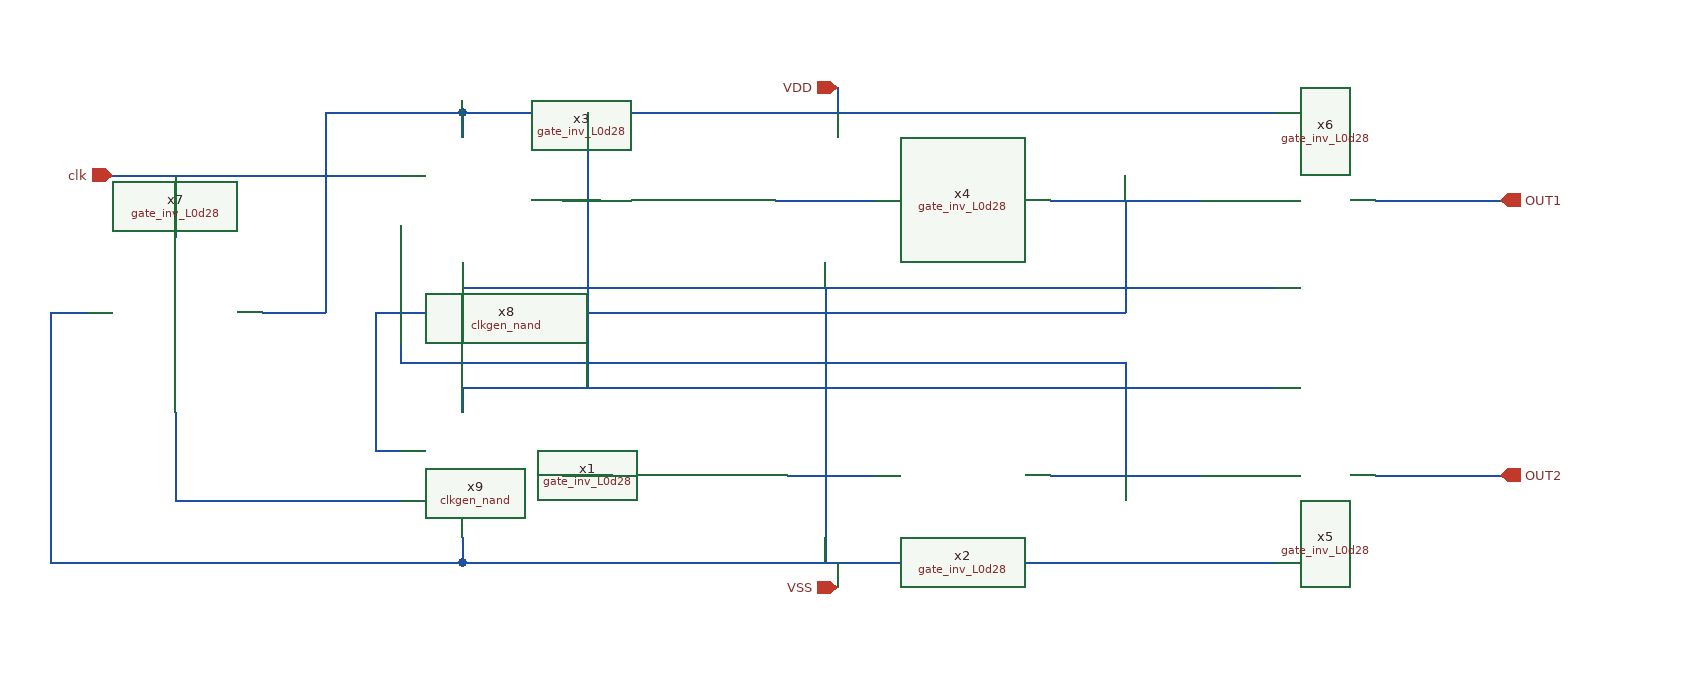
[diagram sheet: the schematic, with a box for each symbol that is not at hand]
v {xschem version=3.4.8RC file_version=1.3}
G {}
K {}
V {}
S {}
F {}
E {}
N 200 -190 280 -190 {lab=#net1}
N 420 -190 540 -190 {lab=#net2}
N 210 30 280 30 {lab=#net3}
N 420 30 540 30 {lab=#net4}
N 680 30 780 30 {lab=OUT2}
N 680 -190 780 -190 {lab=OUT1}
N 130 -40 340 -40 {lab=VDD}
N 340 -40 600 -40 {lab=VDD}
N 340 -120 600 -120 {lab=xxx}
N 120 -120 340 -120 {lab=xxx}
N 120 -260 340 -260 {lab=VDD}
N 340 -260 600 -260 {lab=VDD}
N 130 100 340 100 {lab=xxx}
N 340 100 600 100 {lab=xxx}
N 30 -190 60 -190 {lab=#net5}
N 30 30 70 30 {lab=#net6}
N -50 -260 120 -260 {lab=VDD}
N -50 -260 -50 -240 {lab=VDD}
N -50 -140 -50 -130 {lab=xxx}
N -50 -120 120 -120 {lab=xxx}
N -50 -130 -50 -120 {lab=xxx}
N -50 -40 130 -40 {lab=VDD}
N -50 -40 -50 -20 {lab=VDD}
N -50 100 130 100 {lab=xxx}
N -50 80 -50 100 {lab=xxx}
N -290 -210 -100 -210 {lab=clk}
N -210 50 -100 50 {lab=#net7}
N -120 -100 480 -100 {lab=#net2}
N -120 -80 -120 10 {lab=#net2}
N -120 10 -100 10 {lab=#net2}
N -120 -100 -120 -80 {lab=#net2}
N 480 -190 480 -100 {lab=#net2}
N -280 -210 -280 -160 {lab=clk}
N -330 -210 -290 -210 {lab=clk}
N -280 50 -210 50 {lab=#net7}
N -280 -20 -280 50 {lab=#net7}
N 480 -60 480 30 {lab=#net4}
N -100 -60 480 -60 {lab=#net4}
N -100 -170 -100 -60 {lab=#net4}
N 250 100 250 120 {lab=xxx}
N 250 -280 250 -260 {lab=VDD}
N 50 -260 50 -40 {lab=VDD}
N 240 -120 240 100 {lab=xxx}
N -210 -100 -160 -100 {lab=VDD}
N -160 -260 -160 -100 {lab=VDD}
N -160 -260 -50 -260 {lab=VDD}
N -380 -100 -350 -100 {lab=xxx}
N -380 -100 -380 100 {lab=xxx}
N -380 100 -50 100 {lab=xxx}
C {chipaton/chipa2026_gf180mcu_DeltaSigma/designs/DS_modulator/gate_inv_L0d28/xschem/gate_inv_L0d28.sym} 130 30 0 0 {name=x1}
C {chipaton/chipa2026_gf180mcu_DeltaSigma/designs/DS_modulator/gate_inv_L0d28/xschem/gate_inv_L0d28.sym} 340 30 0 0 {name=x2}
C {chipaton/chipa2026_gf180mcu_DeltaSigma/designs/DS_modulator/gate_inv_L0d28/xschem/gate_inv_L0d28.sym} 120 -190 0 0 {name=x3}
C {chipaton/chipa2026_gf180mcu_DeltaSigma/designs/DS_modulator/gate_inv_L0d28/xschem/gate_inv_L0d28.sym} 340 -190 0 0 {name=x4}
C {chipaton/chipa2026_gf180mcu_DeltaSigma/designs/DS_modulator/gate_inv_L0d28/xschem/gate_inv_L0d28.sym} 600 30 0 0 {name=x5}
C {chipaton/chipa2026_gf180mcu_DeltaSigma/designs/DS_modulator/gate_inv_L0d28/xschem/gate_inv_L0d28.sym} 600 -190 0 0 {name=x6}
C {chipaton/chipa2026_gf180mcu_DeltaSigma/designs/DS_modulator/gate_inv_L0d28/xschem/gate_inv_L0d28.sym} -280 -100 1 0 {name=x7}
C {chipaton/chipa2026_gf180mcu_DeltaSigma/designs/DS_modulator/clkgen/xscheme/clkgen_nand.sym} 50 -90 0 0 {name=x8}
C {chipaton/chipa2026_gf180mcu_DeltaSigma/designs/DS_modulator/clkgen/xscheme/clkgen_nand.sym} 50 130 0 0 {name=x9}
C {ipin.sym} -330 -210 0 0 {name=p1 lab=clk}
C {opin.sym} 780 -190 0 0 {name=p2 lab=OUT1}
C {opin.sym} 780 30 0 0 {name=p3 lab=OUT2}
C {iopin.sym} 250 -280 3 0 {name=p4 lab=VDD}
C {iopin.sym} 250 120 1 0 {name=p5 lab=VSS}
